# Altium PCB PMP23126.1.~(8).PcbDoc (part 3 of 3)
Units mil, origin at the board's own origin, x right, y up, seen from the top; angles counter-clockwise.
Board outline 1315.03 x 1390.8 mil, 6 copper layers (Top Layer, MidLayer1, MidLayer2, MidLayer3, MidLayer4, Bottom Layer), stack 72.6 mil thick; 49 components, 55 nets, 222 pads, 193 vias.
Unrouted connection lines stored in the file: 15.

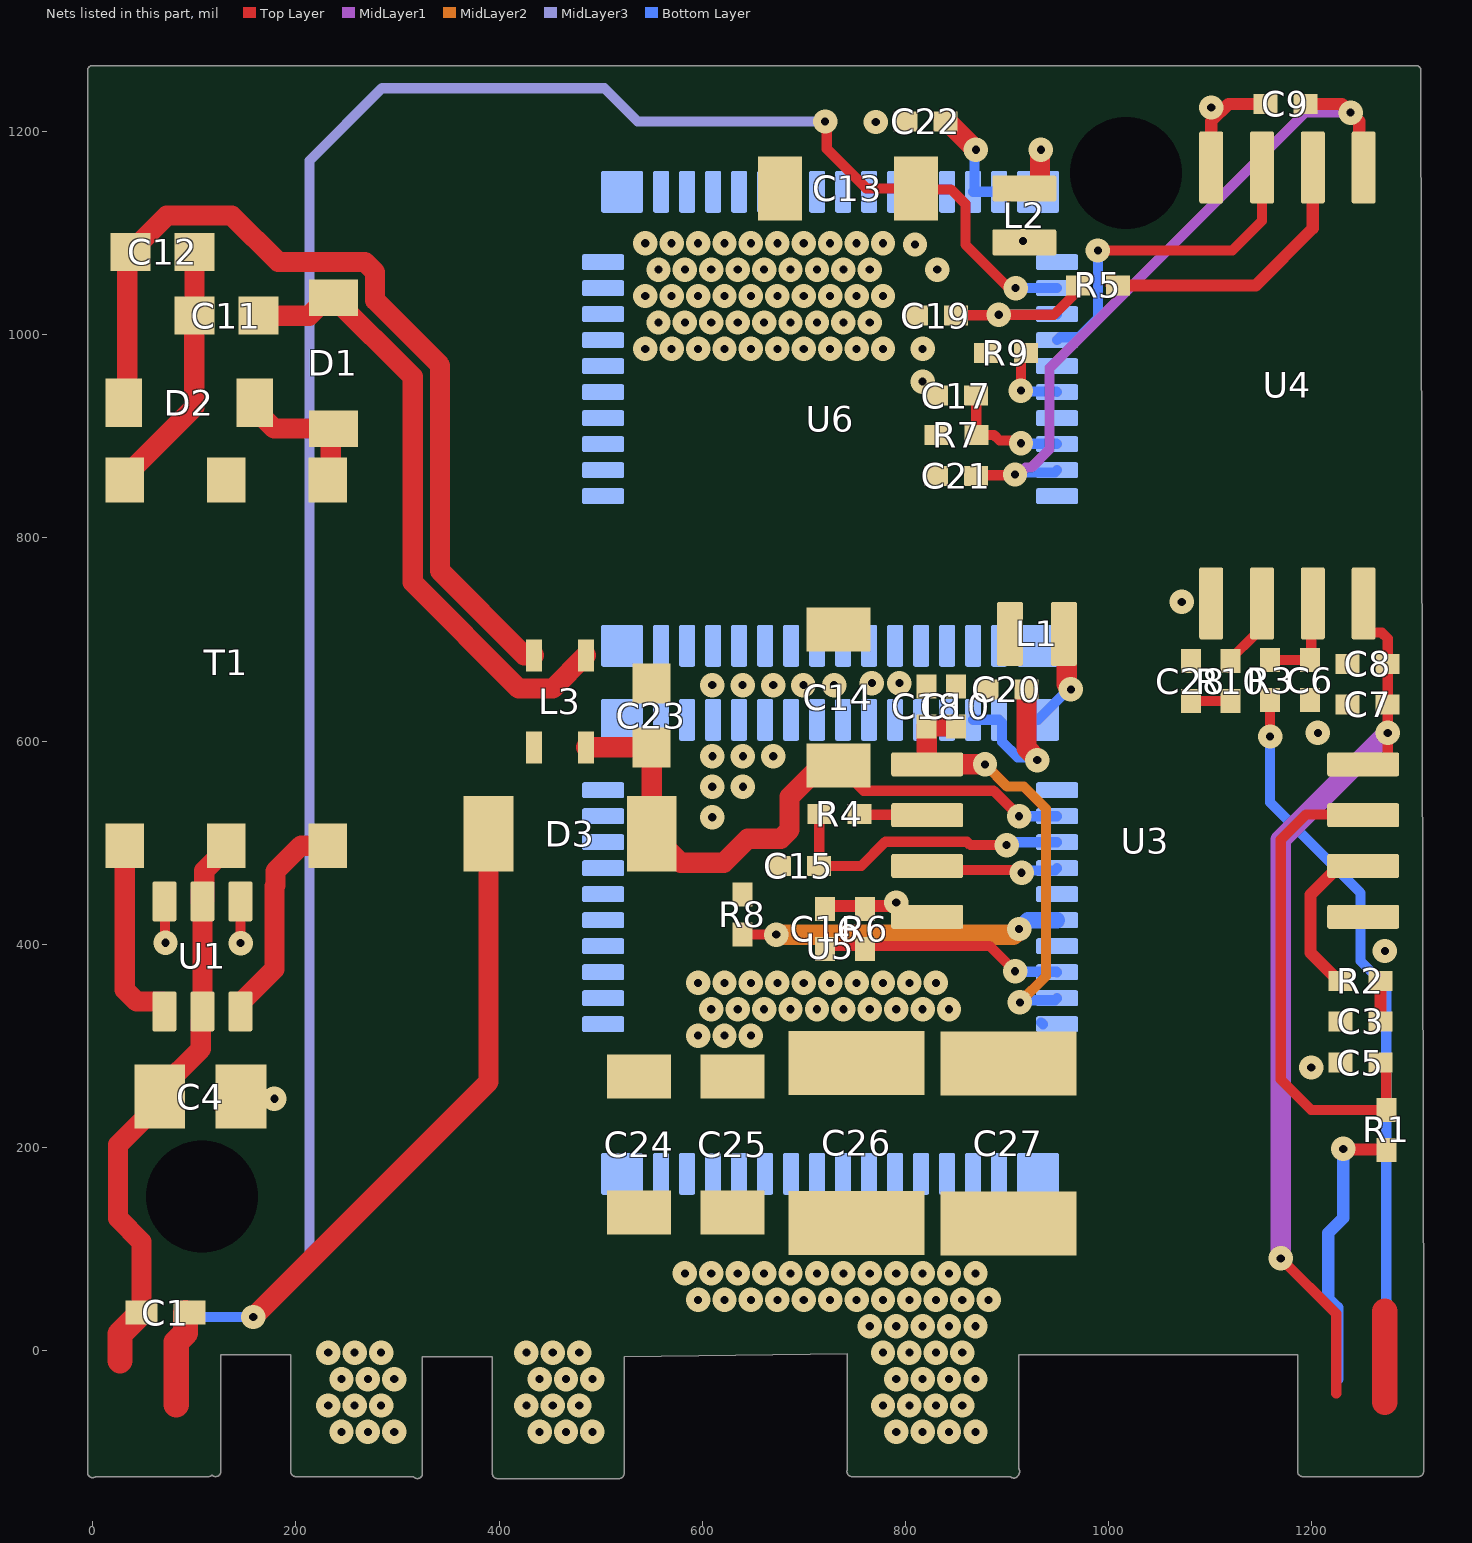
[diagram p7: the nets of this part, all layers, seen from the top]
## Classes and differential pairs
net class INGND: 3.3Vs _Bot_FET_FAULT1 _Top_FET_FAULT1 AGND LEG1_HS LEG1_LS NetC5_1 NetC6_1 NetR2_2 NetR10_2 NetU2_12 NetU3_12
net class PGND: 5V_L1 5Vp 12V FAULT_LS NetC17_2 NetC19_2 NetC22_1 NetL2_2 NetR5_1 NetR9_2 NetT1_4 NetT1_6 NetU2_5 NetU6_43 NetU6_47 NetU6_48 NetU6_52 PGND PGND_NC1 PGND_NC2 PGND_NC3 PGND_NC4 PGND_NC5 TEMP_LS
net class VHV: Vbulk+ VHV_NC1 VHV_NC2
net class VSW1NET: 5V_H1 12V ISO_12V_H1 NCT1 NetC11_1 NetC11_2 NetC12_2 NetC15_2 NetC16_2 NetC20_1 NetD1_2 NetL1_2 NetR4_2 NetR8_2 NetT1_5 NetU3_3 NetU3_5 NetU5_43 NetU5_47 NetU5_48 NetU5_52 SW1 SW1_NC1 SW1_NC2 SW1_NC3 SW1_NC4 SW1_NC5 SW1_NC6 SW1_NC7 TEMP_HS_NC1
component class LMG352X: U5 U6

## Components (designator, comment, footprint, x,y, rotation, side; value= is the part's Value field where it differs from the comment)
C1 "C1005X7R1H104K050BB" 0402 71.69,37.41 r0 top value=0.1uF
C3 "C1005C0G1H680J050BA" 0402L 1248,324.09 r180 top value=68pF
C4 "GCM21BR71C475KA73L" 0805_HV 106,250 r0 top value=4.7uF
C5 "04025A101FAT2A" 0402L 1247.9,283.5 r180 top value=100pF
C6 "04025A101FAT2A" 0402L 1198,660 r270 top value=100pF
C7 "C1005X7R1H104K050BB" 0402L 1255,636 r180 top value=0.1uF
C8 "C1005X7R1H104K050BB" 0402L 1255,676 r0 top value=0.1uF
C9 "C1005X7R1H104K050BB" 0402L 1174,1227 r0 top value=0.1uF
C10 "C1005X7R1H104K050BB" 0402L 849.62,634 r90 top value=0.1uF
C11 "C1608X5R1V475K080AC" 0603 131.62,1018.63 r180 top value=4.7uF
C12 "C1608X5R1V475K080AC" 0603 68.88,1081.48 r180 top value=4.7uF
C13 "C3216X7R1E106M160AE" 1206_190 743.36,1143.96 r180 top value=10uF
C14 "C3216X7R1E106M160AE" 1206_190 734,643 r90 top value=10uF
C15 "04025A101FAT2A" 0402L 695.25,477 r0 top value=100pF
C16 "04025A101FAT2A" 0402L 720.95,415 r270 top value=100pF
C17 "04025A101FAT2A" 0402L 850,940 r0 top value=100pF
C18 "CL05B224KO5NNNC" 0402L 820.93,634 r270 top value=0.22uF
C19 "04025A101FAT2A" 0402L 829.94,1018.63 r0 top value=100pF
C20 "GRT155R61E225KE13D" 0402L 899.5,650.82 r180 top value=2.2uF
C21 "CL05B224KO5NNNC" 0402L 850,861 r0 top value=0.22uF
C22 "GRT155R61E225KE13D" 0402L 820,1210 r180 top value=2.2uF
C23 "C1608X5R1V475K080AC" 0603 550,625 r90 top value=4.7uF
C24 "C1206C223KDRACTU" 1206_190 538,203 r90 top value=0.022uF
C25 "C1206C223KDRACTU" 1206_190 630,203 r90 top value=0.022uF
C26 "C1812W104KDRACTU" 1812_254 752,204.48 r90 top value=0.1uF
C27 "C1812W104KDRACTU" 1812_254 901.45,204 r90 top value=0.1uF
C28 "C1005C0G1H680J050BA" 0402L 1081,659 r90 top value=68pF
D1 "MBR0520LT1G" SOD-123 237,972 r270 top value=20V
D2 "MBR0520LT1G" SOD-123 95,933 r180 top value=20V
D3 "ES1JAF" SMAF 470,508.64 r180 top value=600V
L1 "SDEM20161T-4R7MS" FP-SDEM20161T-4R7MS_SMD2-MFG 929.44,705.4 r0 top
L2 "SDEM20161T-4R7MS" FP-SDEM20161T-4R7MS_SMD2-MFG 917.03,1117.39 r90 top
L3 "ACM2520-601-2P-T002" TDK_ACM2520-2P 460,639.13 r270 top
R1 "RC0402FR-0749R9L" 0402L 1273.29,217.19 r90 top value=49.9
R2 "CRCW0402300RJNED" 0402L 1247.9,364 r180 top value=300
R3 "RC0402FR-0749R9L" 0402L 1159,660 r90 top value=49.9
R4 "RC0402FR-0749R9L" 0402L 735,528 r0 top value=49.9
R5 "RC0402FR-0749R9L" 0402L 989.48,1048.39 r180 top value=49.9
R6 "ERJ-2RKF2003X" 0402L 760,415 r270 top value=200k
R7 "ERJ-2RKF2003X" 0402L 850.08,901.07 r0 top value=200k
R8 "ERJ-2GE0R00X" 0402L 639.59,429.42 r270 top value=0
R9 "ERJ-2GE0R00X" 0402L 899,982 r0 top value=0
R10 "CRCW0402300RJNED" 0402L 1120,659 r90 top value=300
T1 "760390014" Wurth_760390013 131.62,677 r270 top value=475uH
U1 "SN6505BDBVR" DBV0006A_N 108.09,388 r90 top
U3 "ISO7721FDWV" DWV0008A 1036,502 r0 top
U4 "ISO7721FDWV" DWV0008A 1176,950 r270 top
U5 "XMG3522R030QRQSTQ1" RQS0052A-MFG 725.84,397.43 r90 bottom
U6 "XMG3522R030QRQSTQ1" RQS0052A-MFG 725.84,917.17 r90 bottom

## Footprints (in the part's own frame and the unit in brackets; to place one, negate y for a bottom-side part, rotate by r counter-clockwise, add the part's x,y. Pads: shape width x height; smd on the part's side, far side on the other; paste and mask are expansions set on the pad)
0402 [mm] "0402 from SM-752 data"
  rect 0.8x0.6 smd: 1(-0.6,0) 2(0.6,0)
  silkscreen extent -1.22,-0.52 1.22,0.52, body extent -0.55,-0.3 0.55,0.3, height 0.6
0402L [mm] "0402 from SM-752 data"
  rect 0.6x0.5 smd: 1(-0.5,0) 2(0.5,0)
  body extent -0.55,-0.3 0.55,0.3, height 0.6
0603 [mm] "0603 from SM-752 data"
  rect 1x0.95 smd: 1(-0.8,0) 2(0.8,0)
  silkscreen extent -1.52,-0.69 1.52,0.69, body extent -0.87,-0.47 0.87,0.47, height 1
0805_HV [mil] "0805 with 30mil clearance between pads"
  rect 50x63 smd: 1(-40,0) 2(40,0)
  silkscreen extent -74,-40 74,40, body extent -43,-29 43,29, height 57
1206_190 [mm] "1206_190"
  rect 1.1x1.6 smd: 1(-1.7,0) 2(1.7,0)
  silkscreen extent -0.9,-1 0.9,1, body extent -1.75,-0.95 1.75,0.95, height 1.9
1812_254 [mm] "SMD, 2-Leads, Body 4.8x3.4mm"
  rect 1.6x3.4 smd: 1(-2,0) 2(2,0)
  silkscreen extent -0.8,-1.7 0.8,1.7, body extent -2.4,-1.7 2.4,1.7, height 2.54
DBV0006A_N [mm] "SOT23, 6-Leads, Body 2.9x1.6mm, Pitch 0.95mm, Lead Span 2.8mm, IPC Medium Density"
  rrect17% 1x0.6 smd: 1(-1.375,0.95) 2(-1.375,0) 3(-1.375,-0.95) 4(1.375,-0.95) 5(1.375,0) 6(1.375,0.95)
  silkscreen extent -1.68,-1.55 0.5,1.55, body extent -1.42,-1.46 1.42,1.46, height 1.12
DWV0008A [mm] "SOIC, 8-Leads, Body 5.95x7.6mm (max), Pitch 1.27mm"
  rrect17% 1.8x0.6 smd: 1(-5.45,1.905) 2(-5.45,0.635) 3(-5.45,-0.635) 4(-5.45,-1.905) 5(5.45,-1.905) 6(5.45,-0.635) 7(5.45,0.635) 8(5.45,1.905)
  silkscreen extent -6.25,-2.95 2.98,2.95, body extent -5.77,-2.92 5.77,2.93, height 2.67
FP-SDEM20161T-4R7MS_SMD2-MFG [mm]
  rrect15% 0.65x1.6 smd paste+0 mask+0: 1(-0.675,0) 2(0.675,0)
  silkscreen extent -1.05,-1.22 1.05,1.2, body extent -1.15,-0.95 1.15,0.95, height 0.25
RQS0052A-MFG [mm]
  rrect10% 1.05x1.05 smd paste+0 mask+0: 1(-5.675,5.2) 16(-5.675,-5.2) 27(5.675,-5.2) 42(5.675,5.2)
  rrect25% 1.05x0.4 smd paste+0 mask+0: 2(-5.675,4.225) 3(-5.675,3.575) 4(-5.675,2.925) 5(-5.675,2.275) 6(-5.675,1.625) 7(-5.675,0.975) 8(-5.675,0.325) 9(-5.675,-0.325) 10(-5.675,-0.975) 11(-5.675,-1.625) 12(-5.675,-2.275) 13(-5.675,-2.925) 14(-5.675,-3.575) 15(-5.675,-4.225) 28(5.675,-4.225) 29(5.675,-3.575) 30(5.675,-2.925) 31(5.675,-2.275) 32(5.675,-1.625) 33(5.675,-0.975) 34(5.675,-0.325) 35(5.675,0.325) 36(5.675,0.975) 37(5.675,1.625) 38(5.675,2.275) 39(5.675,2.925) 40(5.675,3.575) 41(5.675,4.225)
  rrect25% 0.4x1.05 smd paste+0 mask+0: 17(-1.935,-5.675) 18(-1.285,-5.675) 19(-0.635,-5.675) 20(0.015,-5.675) 21(0.665,-5.675) 22(1.315,-5.675) 23(1.965,-5.675) 24(2.615,-5.675) 25(3.265,-5.675) 26(3.915,-5.675) 43(3.915,5.675) 44(3.265,5.675) 45(2.615,5.675) 46(1.965,5.675) 47(1.315,5.675) 48(0.665,5.675) 49(0.015,5.675) 50(-0.635,5.675) 51(-1.285,5.675) 52(-1.935,5.675)
  silkscreen extent -6.9,-6.05 4.77,6.05, body extent -6,-6 6,6, height 1
SMAF [mm] "SMD, 2-Leads, Body 3.8x2.5mm"
  rect 1.24x1.89 smd: 1(-2.04,0) 2(2.04,0)
  silkscreen extent -3.4,-1.3 2.8,1.3, body extent -2.35,-1.25 2.35,1.25, height 1
SOD-123 [mm] "On Semi recommended land pattern"
  rect 0.915x1.22 smd: 1(-1.637,0) 2(1.637,0)
  silkscreen extent -2.74,-1.17 2.03,1.17, body extent -1.93,-0.9 1.93,0.9, height 1.35
TDK_ACM2520-2P [mm] "SMD, 4-Leads, Body 2.5x2mm"
  rect 0.8x0.4 smd: 1(-1.15,0.65) 2(-1.15,-0.65) 3(1.15,-0.65) 4(1.15,0.65)
  silkscreen extent -1.45,-1.2 1.45,1.4, body extent -1.35,-1.1 1.35,1.1, height 1.3
Wurth_760390013 [mil] "Wurth"
  rect 44x38 smd: 1(-180,100) 2(-180,0) 3(-180,-100) 4(180,-100) 5(180,0) 6(180,100)
  silkscreen extent -190,-133 85,145, body extent -198,-135 198,130, height 166

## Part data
C1 C7 C8 C9 C10: library part CMP-0006297-2, "CAP, CERM, 0.1 uF, 50 V, +/- 10%, X7R, 0402", Alternate Manufacturer="Wurth Elektronik", Alternate PartNumber=885012205037, Cap_Case=0402, Manufacturer=TDK, Supplier Part Number 1=445-5932-1-ND, TempCo=X7R, Tolerance_%=10%, Value1="0.039064 ohm", Value2=50V, ValueDisplayed=0.1uF
C3 C28: library part CMP-0006251-2, "CAP, CERM, 68 pF, 50 V, +/- 5%, C0G/NP0, 0402", Alternate Manufacturer=Murata, Alternate PartNumber=GRM1555C1H680JA01D, Cap_Case=0402, Manufacturer=TDK, Supplier Part Number 1=445-1245-1-ND, TempCo=C0G/NP0, Tolerance_%=5%, Value1=Unknown, Value2=50V, ValueDisplayed=68pF
C4: library part CMP-0008020-2, "CAP, CERM, 4.7 uF, 16 V, +/- 10%, X7R, AEC-Q200 Grade 1, 0805", Cap_Case=0805, Manufacturer=MuRata, Supplier Part Number 1=490-5332-1-ND, TempCo=X7R, Tolerance_%=10%, Value1=Unknown, Value2=16V, ValueDisplayed=4.7uF
C5 C6 C15 C16 C17 C19: library part CMP-0006196-2, "CAP, CERM, 100 pF, 50 V, +/- 1%, C0G/NP0, 0402", Cap_Case=0402, Manufacturer=AVX, Supplier Part Number 1=478-3658-1-ND, TempCo=C0G/NP0, Tolerance_%=1%, Value1=Unknown, Value2=50V, ValueDisplayed=100pF
C11 C12 C23: library part CMP-0007022-5, "CAP, CERM, 4.7 uF, 35 V, +/- 10%, X5R, 0603", Cap_Case=0603, Manufacturer=TDK, Supplier Part Number 1=445-9064-1-ND, TempCo=X5R, Tolerance_%=10%, Value1="0.003728 ohm", Value2=35V, ValueDisplayed=4.7uF
C13 C14: library part CMP-0008692-2, "CAP, CERM, 10 uF, 25 V, +/- 20%, X7R, 1206_190", Cap_Case=1206, Manufacturer=TDK, Supplier Part Number 1=445-6812-1-ND, TempCo=X7R, Tolerance_%=20%, Value1=Unknown, Value2=25V, ValueDisplayed=10uF
C18 C21: library part CMP-0860563-1, "CAP, CERM, 0.22 µF, 16 V,+/- 10%, X7R, 0402", Cap_Case=0402, Manufacturer="Samsung Electro-Mechanics", TempCo=X7R, Tolerance_%=10%, Value2=16V, ValueDisplayed=0.22µF
C20 C22: library part CMP-0006716-2, "CAP, CERM, 2.2 uF, 25 V, +/- 10%, X5R, AEC-Q200 Grade 3, 0402", Cap_Case=0402, Manufacturer=MuRata, Supplier Part Number 1=490-12267-1-ND, TempCo=X5R, Tolerance_%=10%, Value1=Unknown, Value2=25V, ValueDisplayed=2.2uF
C24 C25: library part CMP-0084048-1, "CAP, CERM, 0.022 µF, 1000 V,+/- 10%, X7R, AEC-Q200 Grade 1, 1206", Cap_Case=1206, Manufacturer=Kemet, TempCo=X7R, Tolerance_%=10%, Value2=1000V, ValueDisplayed=0.022µF
C26 C27: library part CMP-0009326-2, "CAP, CERM, 0.1 uF, 1000 V, +/- 10%, X7R, 1812", Cap_Case=1812, Manufacturer=Kemet, Supplier Part Number 1=399-6523-1-ND, TempCo=X7R, Tolerance_%=10%, Value1=Unknown, Value2=1000V, ValueDisplayed=0.1uF
D1 D2: library part CMP-0028524-2, "Diode, Schottky, 20 V, 0.5 A, SOD-123", Manufacturer="ON Semiconductor", Value1=0.5A, Value2=0.385V
D3: library part CMP-0029162-2, "Diode, Ultrafast, 600 V, 1 A, AEC-Q101, SMAF", Manufacturer="Fairchild Semiconductor", Value1=1A, Value2=1.7V
L1 L2: library part CMP-0089347-1, "4.7µH Unshielded Inductor 1.1A 426mOhm Max 0806 (2016 Metric)", Digikey Part Number=2037-SDEM20161T-4R7MSCT-ND, Manufacturer=Cyntec, Operating Temperature Range="-55°C to +125°C", Test Frequency=1MHz, Tolerance_%=20%
L3: library part CMP-0013161-2, "Coupled inductor, 0.2 A, 0.45 ohm, SMD", Manufacturer=TDK, Supplier Part Number 1=445-8930-1-ND
R1 R3 R4 R5: library part CMP-0026738-1, "RES, 49.9, 1%, 0.063 W, 0402", Manufacturer="Yageo America", Power_W=63mW, Supplier Part Number 1=311-49.9LRCT-ND, TempCo="100 ppm/C", Tolerance_%=1%, Value2=0.063W, Value_Code=49R9, ValueDisplayed=49.9
R2 R10: library part CMP-0026902-3, "RES, 300, 5%, 0.063 W, AEC-Q200 Grade 0, 0402", Manufacturer=Vishay-Dale, Power_W=63mW, Supplier Part Number 1=541-300JCT-ND, TempCo="200 ppm/C", Tolerance_%=5%, Value2=0.063W, Value_Code=300R, ValueDisplayed=300
R6 R7: library part CMP-0026677-1, "RES, 200 k, 1%, 0.1 W, 0402", Manufacturer=Panasonic, Power_W=100mW, Supplier Part Number 1=P200KLCT-ND, TempCo="100 ppm/C", Tolerance_%=1%, Value2=0.1W, Value_Code=200k
R8 R9: library part CMP-0026992-3, "RES, 0, 5%, 0.1 W, AEC-Q200 Grade 0, 0402", Manufacturer=Panasonic, Power_W=100mW, Supplier Part Number 1=P0.0JCT-ND, TempCo="600 ppm/C", Tolerance_%=5%, Value2=0.1W, Value_Code=0000, ValueDisplayed=0
T1: library part CMP-0030718-1, "Transformer, 475uH, SMT", Manufacturer="Wurth Elektronik", Supplier Part Number 1=732-4458-1-ND, ValueDisplayed=475uH
U1: library part CMP-0076095-1, "Low-Noise 1 A, 420 kHz Transformer Driver, DBV0006A (SOT-23-6)", Alternate Manufacturer="Texas Instruments", Alternate PartNumber=SN6505BDBVT
U3 U4: library part CMP-0085676-1, "High Speed, Robust EMC Reinforced Dual-Channel Digital Isolator, DWV0008A (SOIC-8)", Alternate Manufacturer="Texas Instruments", Alternate PartNumber=ISO7721FDWVR, Operating Temperature Range="-55 to 125 C", Rating=Catalog
U5 U6: library part CMP-0092112-1, "650-V 30-mΩ GaN FET with Integrated Driver, Protection, and Temperature Reporting", Manufacturer="Texas Instruments", Max Supply Voltage=18V, Min Supply Voltage=7.5V, Nominal Supply Current=700-16000uA, Operating Temperature Range="-40°C to +125°C", Output Voltage=520V, PartNumber=XMG3522R050QRQSTQ1

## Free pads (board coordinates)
  round 60 hole 110.24: 1(107.5,151.54) 1(1017,1159.25)

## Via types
v1: diameter 24, hole 8, Top Layer to Bottom Layer, 140 vias
v2: diameter 24, hole 8, Top Layer to Bottom Layer, tented both sides, 53 vias

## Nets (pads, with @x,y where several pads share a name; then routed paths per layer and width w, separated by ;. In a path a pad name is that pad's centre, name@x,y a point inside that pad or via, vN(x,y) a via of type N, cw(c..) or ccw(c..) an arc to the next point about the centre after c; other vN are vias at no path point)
3.3Vs: C7.1 C8.2 U3.8 U4.8 | length 911
  Top Layer w10: v2(1169.47,90.73) 1224,36.2 1224,-42 ; U3.8@1250.57,577 1267.87,577 1274.68,583.81 v2(1274.68,608) C7.1@1274.68,636 C8.2@1274.69,676 1274.69,700.84 1268.83,706.7 1257.81,706.7 1251,713.51 U4.8@1251,735.43
  MidLayer1 w20: v2(1169.47,90.73) 1169.47,502.79 v2(1274.68,608)
5V_H1: C10.1 C18.2 U3.1 U5.51 | length 440.9
  Top Layer w20: C10.1@849.62,614.32 C18.2@820.93,614.31 820.93,577.5 U3.1@821.43,577 v2(878.36,577)
  MidLayer2 w10: v2(878.36,577) 900.24,555.12 916.76,555.12 938.4,533.48 938.4,368.48 v2(912.66,342.74)
  Bottom Layer w10: v2(912.66,342.74) 914.7,344.79 947.22,344.79 U5.51@949.27,346.83
5V_L1: C9.2 C21.2 U4.1 U6.51 | length 713.8
  Top Layer w10: C21.2@869.69,861 870.32,861.64 907.2,861.64 v2(907.84,862.28)
  Top Layer w12: C9.2@1193.69,1227 1229.69,1227 v2(1238.19,1218.5) 1246.69,1210 1246.69,1168.88 U4.1@1251,1164.57
  MidLayer1 w10: v2(907.84,862.28) 911.63,862.28 918.43,869.08 923.76,869.08 941.84,887.16 941.84,967 1193.34,1218.5 v2(1238.19,1218.5)
  Bottom Layer w10: v2(907.84,862.28) 909.99,864.43 947.12,864.43 U6.51@949.27,866.58
5Vp: C1.1 C4.1 T1.5 U1.2 U1.5 | length 571.9
  Top Layer w20: C1.1@48.07,37.41 48.07,107.19 25,130.26 25,202.5 66,243.5 C4.1@66,250 66,256.5 106.28,296.78 106.28,324.18 U1.2@108.09,325.99 ; U1.5@106.38,442.13 U1.5@106.38,452.44 ; U1.2@108.09,333.87 U1.5@108.09,442.13 109.91,443.94 109.91,472.28 131.62,494 T1.5@131.62,497
  Top Layer w25: 27,-10 27,16.34 C1.1@48.07,37.41
12V: C13.1 D3.2 U6.44 | length 2744.8
  Top Layer w10: v2(720.95,1209.8) 722.63,1208.12 722.63,1182.8 761.47,1143.96 C13.1@810.29,1143.96 811.3,1142.95 844.91,1142.95 859.04,1128.82 859.04,1088.67 899.32,1048.39 905.74,1048.39 v2(908.42,1045.71)
  Top Layer w20: v2(158.08,33.03) 389.69,264.63 D3.2@389.69,508.64
  MidLayer3 w10: v2(158.08,33.03) 158.08,35.61 213.47,91 213.47,1171.28 284.69,1242.5 503.76,1242.5 536.46,1209.8 v2(720.95,1209.8)
  Bottom Layer w10: 84.19,-28.03 82.7,-26.54 82.7,15.75 99.98,33.03 v2(158.08,33.03) ; v2(908.42,1045.71) U6.44@949.27,1045.71
_Bot_FET_FAULT1: C28.1 R10.1 | length 39.3
  Top Layer w10: C28.1@1081.19,639.13 C28.1@1081,639.32 R10.1@1120,639.32
_Top_FET_FAULT1: C3.1 R2.1 | length 40
  Top Layer w12: R2.1@1267.58,364 1267.63,363.95 1267.63,324.14 C3.1@1267.68,324.09
AGND: C3.2 C5.2 C6.2 C7.2 C8.1 C28.2 U3.5 U4.5 | length 89.6
  Top Layer w25: 1271.9,-51 1271.9,38.61
  other v2: 1199.5,278.66 1271.9,393.35 1206,608 1072,737
FAULT_LS: U4.3 U6.46 | length 342.1
  Top Layer w10: v2(989.48,1082.82) 1121.82,1082.82 1151,1112 U4.3@1151,1164.57
  Bottom Layer w10: U6.46@949.27,994.53 952.14,997.4 970.91,997.4 989.48,1015.97 v2(989.48,1082.82)
ISO_12V_H1: C14.1 C23.1 D3.1 L3.4 U5.44 | length 639.9
  Top Layer w10: C14.1@734,576.07 759,551.08 886.86,551.08 v2(911.96,525.97)
  Top Layer w20: L3.4@485.59,593.85 549.65,593.85 C23.1@550,593.5 550.31,593.19 D3.1@550.31,508.64 578.87,480.09 621.07,480.09 644.82,503.84 677.32,503.84 685.98,512.51 685.98,545 717.05,576.07 C14.1@734,576.07
  Bottom Layer w10: v2(911.96,525.97) U5.44@949.27,525.97
LEG1_HS: R1.1 | length 279.8
  Top Layer w12: v2@1231.1,198.75 v2(1230.88,198.54) 1231.4,198.02 1272.78,198.02 R1.1@1273.29,197.5 R1.1@1273.51,197.29
  Bottom Layer w12: 1225,-28.03 1225,42.21 1216.2,51.01 1216.2,115.81 1230.88,130.49 v2(1230.88,198.54)
LEG1_LS: R3.1 | length 712.6
  Top Layer w10: v2(1159,604.48) R3.1@1159,640.32
  Bottom Layer w10: v2(1159,604.48) 1159,539.47 1247.9,450.57 1247.9,383.41 1273.29,358.02 1273.29,-24.96
NCT1: T1.2
NetC5_1: C5.1 R1.2 U3.7 | length 493.8
  Top Layer w10: U3.7@1250.57,527 1249.76,527.81 1194.49,527.81 1169.47,502.79 1169.47,266.86 1199.46,236.87 R1.2@1273.29,236.87 1273.29,278.66 1268.45,283.5 C5.1@1267.58,283.5 C5.1@1267.8,283.28
NetC6_1: C6.1 R3.2 U4.7 | length 98.1
  Top Layer w10: R3.2@1159,679.69 C6.1@1198,679.68 1199.5,681.18 1199.5,733.93 U4.7@1201,735.43 U4.7@1199.5,736.93
NetC11_1: C11.1 D1.1 L3.1 | length 621.3
  Top Layer w20: C11.1@163.12,1018.63 213.15,1018.63 231,1036.47 D1.1@237,1036.47 315,958.47 315,756.15 419.49,651.66 452.84,651.66 L3.1@485.59,684.4
NetC11_2: C11.2 C12.1 T1.3 | length 256.8
  Top Layer w20: T1.3@31.62,857 31.62,860 100.13,928.5 C11.2@100.13,1018.63 100.25,1018.75 100.25,1081.35 C12.1@100.38,1081.48 C12.1@103.07,1078.79
NetC12_2: C12.2 D2.2 L3.2 | length 877.2
  Top Layer w20: D2.2@30.53,933 33.96,936.43 33.96,1078.05 C12.2@37.39,1081.48 73.09,1117.18 137.06,1117.18 182.76,1071.48 268.06,1071.48 278.02,1061.52 278.02,1033.64 342,969.65 342,767.33 424.93,684.4 L3.2@434.41,684.4
NetC15_2: C15.2 R4.1 U5.45 | length 300.7
  Top Layer w10: R4.1@709.38,530 R4.1@711.38,528 ; R4.1@715.31,528 715.13,527.81 715.13,477.19 C15.2@714.94,477 756.48,477 780.29,500.81 860.66,500.81 863.92,497.55 v2(899.58,497.55)
  Bottom Layer w10: v2(899.58,497.55) 903.37,497.55 906.2,500.38 U5.45@949.27,500.38
NetC16_2: C16.2 R6.2 U5.50 | length 241.9
  Top Layer w10: C16.2@720.95,391.38 C16.2@722.95,389.38 ; C16.2@720.95,398.31 760,398.31 883,398.31 v2(907.94,373.38)
  Bottom Layer w10: v2(907.94,373.38) 908.42,372.9 948.79,372.9 U5.50@949.27,372.43
NetC17_2: C17.2 R7.2 U6.50 | length 122.2
  Top Layer w10: R7.2@869.69,901 C17.2@869.69,940 ; R7.2@871.54,901.08 887.29,901.08 892.61,895.76 911.14,895.76 v2(913.82,893.08)
  Bottom Layer w10: v2@911.96,893 912.38,892.58 948.85,892.58 U6.50@949.27,892.17
NetC19_2: C19.2 R5.2 U6.45 | length 189.2
  Top Layer w10: C19.2@850.04,1018.21 C19.2@849.62,1018.63 850.08,1019.08 891.36,1019.08 v2(891.81,1019.53) 946.32,1019.53 R5.2@969.8,1043.01 ; R5.2@969.8,1048.39 R5.2@970.21,1047.97
  Bottom Layer w10: v2(891.81,1019.53) 892.1,1019.83 948.97,1019.83 U6.45@949.27,1020.12
NetC20_1: C20.1 U5.40 U5.41 | length 164.6
  Top Layer w20: C20.1@919.18,650.82 919.18,592.82 929.74,582.26 v2(929.74,581.18)
  Bottom Layer w10: U5.40@866.59,620.85 U5.41@892.18,620.85 895.06,617.98 895.06,599.26 910.46,583.86 927.06,583.86 v2(929.74,581.18)
NetC22_1: C22.1 U6.40 U6.41 | length 109.4
  Top Layer w20: C22.1@839.69,1210 841.34,1210 v2@869.31,1182.03
  Bottom Layer w10: v2(869.31,1182) 867.95,1180.64 867.95,1141.95 U6.40@866.59,1140.59 U6.41@892.18,1140.59
NetD1_2: D1.2 D2.1 T1.1 | length 144.4
  Top Layer w20: D2.1@159.47,933 159.47,927 178.93,907.53 D1.2@237,907.53 234.31,904.84 234.31,859.69 T1.1@231.62,857
NetL1_2: L1.2 U5.42 | length 125.8
  Top Layer w20: L1.2@958.81,726.9 956.02,724.1 L1.2@956.02,705.4 958.81,702.61 958.81,655.94 962.85,651.9 v2(962.85,650.82) v2@962.09,651.58
  Bottom Layer w10: U5.42@930.57,620.85 960.54,650.82 v2(962.85,650.82)
NetL2_2: L2.2 U6.42 | length 94.7
  Top Layer w20: L2.2@917.03,1143.96 929.72,1143.96 932.52,1146.76 932.52,1181.23 v2(933.28,1182)
  Bottom Layer w10: U6.42@930.57,1140.59 933.28,1143.31 v2(933.28,1182)
NetR2_2: R2.2 U3.6 | length 161.7
  Top Layer w12: R2.2@1228.21,364 1226.25,364 1198.69,391.56 1198.69,448.74 1226.94,477 U3.6@1250.57,477
NetR4_2: R4.2 U3.2 | length 67.2
  Top Layer w10: R4.2@754.69,528 755.19,527.5 820.93,527.5 U3.2@821.43,527
NetR5_1: R5.1 U4.2 | length 281.2
  Top Layer w12: R5.1@1003.08,1048.39 1144.78,1048.39 1201,1104.61 U4.2@1201,1164.57
NetR8_2: R8.2 U5.48 | length 319.6
  Top Layer w10: R8.2@639.38,409.95 R8.2@639.59,409.73 639.75,409.58 672.7,409.58 v2(672.86,409.42) v2@673.07,409.63
  MidLayer2 w10: v2@672,415 v2@672.86,415
  MidLayer2 w20: v2(672.86,409.42) 906.38,409.42 v2(911.96,415)
  Bottom Layer w10: U5.48@947.57,425.3 U5.48@949.27,423.61
  Bottom Layer w16: v2(911.96,415) 920.57,423.61 U5.48@949.27,423.61
NetR9_2: R9.2 U6.48 | length 75.6
  Top Layer w10: v2(913.66,944.84) 913.66,977.16 918.5,982 R9.2@918.69,982
  Bottom Layer w10: v2(913.66,944.84) 914.41,944.09 948.52,944.09 U6.48@949.27,943.35
NetR10_2: R10.2 U4.6 | length 69.6
  Top Layer w10: R10.2@1120,678.69 1120,680.65 1144.19,704.84 1144.19,728.62 U4.6@1151,735.43
NetT1_4: T1.4 U1.1 | length 194.3
  Top Layer w20: T1.4@31.62,497 31.62,355.27 43.34,343.55 68.88,343.55 70.69,341.74 U1.1@70.69,333.87
NetT1_6: T1.6 U1.3 | length 214.4
  Top Layer w20: U1.3@145.5,333.87 145.5,341.74 178.96,375.2 178.96,456.96 180,458 180,471.91 205.09,497 T1.6@231.62,497
NetU3_3: U3.3 U5.46 | length 132.5
  Top Layer w10: U3.3@821.43,477 825.44,473 911.72,473 v2(914.4,470.32)
  Bottom Layer w10: v2(914.4,470.32) 916.63,472.55 947.03,472.55 U5.46@949.27,474.79
PGND: C1.2 C4.2 C9.1 C13.2 C17.1 C19.1 C21.1 C22.2 C24.2 C25.2 C26.2 C27.2 L2.1 R7.1 R9.1 U1.4 U1.6 U4.4 U6.18 U6.19 U6.20 U6.21 U6.22 U6.23 U6.24 U6.25 U6.26 U6.28 U6.29 U6.30 U6.31 U6.32 U6.33 U6.34 U6.35 U6.36 U6.37 U6.38 U6.39 | length 294.9
  Top Layer w10: U1.6@70.69,442.13 71.19,441.63 71.19,402 v2(71.69,401.5) ; U1.4@145.5,442.13 145.6,442.03 145.6,401.18 v2(145.71,401.07)
  Top Layer w12: C1.2@95.32,37.41 C1.2@99.9,32.83 ; U4.4@1101,1164.57 1101,1210 1118,1227 C9.1@1154.32,1227
  Top Layer w20: C1.2@91.38,37.41 C1.2@95.32,37.41 ; v2(915.78,1092.07) L2.1@917.03,1090.81
  Top Layer w25: 82.46,-53.28 82.46,8.46 91.38,17.38 C1.2@91.38,37.41
  Bottom Layer w10: 146,347 146.25,347.25
  other v1: 439.94,-80.03 465.94,-80.03 491.94,-80.03 426.94,-54.03 452.94,-54.03 478.94,-54.03 439.94,-28.03 465.94,-28.03 491.94,-28.03 426.94,-2.03 452.94,-2.03 478.94,-2.03 595.94,309.97 621.94,309.97 647.94,309.97 608.94,335.97 634.94,335.97 660.94,335.97 686.94,335.97 712.94,335.97 738.94,335.97 764.94,335.97 790.94,335.97 816.94,335.97 842.94,335.97 595.94,361.97 621.94,361.97 647.94,361.97 673.94,361.97 699.94,361.97 725.94,361.97 751.94,361.97 777.94,361.97 803.94,361.97 829.94,361.97 543.94,985.97 569.94,985.97 595.94,985.97 621.94,985.97 647.94,985.97 673.94,985.97 699.94,985.97 725.94,985.97 751.94,985.97 777.94,985.97 556.94,1011.97 582.94,1011.97 608.94,1011.97 634.94,1011.97 660.94,1011.97 686.94,1011.97 712.94,1011.97 738.94,1011.97 764.94,1011.97 543.94,1037.97 569.94,1037.97 595.94,1037.97 621.94,1037.97 647.94,1037.97 673.94,1037.97 699.94,1037.97 725.94,1037.97 751.94,1037.97 777.94,1037.97 556.94,1063.97 582.94,1063.97 608.94,1063.97 634.94,1063.97 660.94,1063.97 686.94,1063.97 712.94,1063.97 738.94,1063.97 764.94,1063.97 543.94,1089.97 569.94,1089.97 595.94,1089.97 621.94,1089.97 647.94,1089.97 673.94,1089.97 699.94,1089.97 725.94,1089.97 751.94,1089.97 777.94,1089.97
  other v2: 178.93,247.88 816.94,953.78 816.94,985.97 831.31,1063.97 809.43,1088.67 770.86,1209.3 1101,1223.51
PGND_NC1: U6.17
PGND_NC2: U6.27
PGND_NC3: U6.43
PGND_NC4: U6.47
PGND_NC5: U6.52
SW1: C10.2 C14.2 C15.1 C16.1 C18.1 C20.2 C23.2 L1.1 L3.3 R6.1 R8.1 U3.4 U5.18 U5.19 U5.20 U5.21 U5.22 U5.23 U5.24 U5.25 U5.26 U5.28 U5.29 U5.30 U5.31 U5.32 U5.33 U5.34 U5.35 U5.36 U5.37 U5.38 U5.39 U6.2 U6.3 U6.4 U6.5 U6.6 U6.7 U6.8 U6.9 U6.10 U6.11 U6.12 U6.13 U6.14 U6.15 | length 107.1
  Top Layer w12: C16.1@720.95,437.68 760,437.68 767.29,437.68 787.13,437.68 797.81,427 U3.4@821.43,427 ; C20.2@873.74,650.82 C20.2@875.88,650.82
  other v1: 244.94,-80.03 270.94,-80.03 296.94,-80.03 231.94,-54.03 257.94,-54.03 283.94,-54.03 244.94,-28.03 270.94,-28.03 296.94,-28.03 231.94,-2.03 257.94,-2.03 283.94,-2.03
  other v2: 790.94,441 609.89,525 609.89,554.95 640,554.95 610,585 640,585 669.89,585 609.89,655 639.83,655 669.89,655 699.52,655 729.79,655 766.94,657 794,657
SW1_NC1: U5.17
SW1_NC2: U5.27
SW1_NC3: U5.43
SW1_NC4: U5.47
SW1_NC5: U5.52 | length 2.6
  Bottom Layer w10: U5.52@933.6,323.09 U5.52@935.44,321.24
SW1_NC6: U6.1
SW1_NC7: U6.16
TEMP_HS_NC1: U5.49
TEMP_LS: U6.49
Vbulk+: C24.1 C25.1 C26.1 C27.1 U5.2 U5.3 U5.4 U5.5 U5.6 U5.7 U5.8 U5.9 U5.10 U5.11 U5.12 U5.13 U5.14 U5.15
  other v1: 790.94,-80.03 816.94,-80.03 842.94,-80.03 868.94,-80.03 777.94,-54.03 803.94,-54.03 829.94,-54.03 855.94,-54.03 790.94,-28.03 816.94,-28.03 842.94,-28.03 868.94,-28.03 777.94,-2.03 803.94,-2.03 829.94,-2.03 855.94,-2.03 764.94,23.97 790.94,23.97 816.94,23.97 842.94,23.97 868.94,23.97 595.94,49.97 621.94,49.97 647.94,49.97 673.94,49.97 699.94,49.97 725.94,49.97 751.94,49.97 777.94,49.97 803.94,49.97 829.94,49.97 855.94,49.97 881.94,49.97 582.94,75.97 608.94,75.97 634.94,75.97 660.94,75.97 686.94,75.97 712.94,75.97 738.94,75.97 764.94,75.97 790.94,75.97 816.94,75.97 842.94,75.97 868.94,75.97
VHV_NC1: U5.1
VHV_NC2: U5.16

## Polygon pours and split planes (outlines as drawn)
PGND on Bottom Layer "PGND_L06_P098" (solid, remove dead copper, pour order 98): 1119.01,1063.99 1002.06,1063.99 891.52,951 831.31,951 831.31,1259.84 1158.08,1259.84 1158.08,1103.06
Vbulk+ on Bottom Layer "VBULK+_L06_P077" (solid, remove dead copper, pour order 77): 532.18,202.12 499.28,169.21 499.28,84.85 582.94,1.19 583.75,2 747.81,2 747.81,-116.6 751.64,-120.43 906.71,-120.43 906.71,-0.23 907.94,1 979.32,1 979.32,168.74 945.94,202.12
PGND on Bottom Layer "PGND_L06_P065" (solid, remove dead copper, pour order 65): 495,14.13 523.17,-14.04 523.17,-119 390.96,-119 390.96,-0.93 404.94,-0.93 420,14.13
AGND on Bottom Layer "AGND_L06_P061" (solid, remove dead copper, pour order 61): 1027.98,724.65 1030.65,724.65 1060,754 1277,754 1307,724 1290,707 1290,5.98 1027.98,5.98
SW1 on Bottom Layer "SW1_L06_P048" (solid, pour order 48): 293,14.13 353,-45.87 352.48,-51.23 352.48,-119 192.48,-119 192.48,-20.39 227,14.13
SW1 on Bottom Layer "SW1_L06_P036" (solid, remove dead copper, pour order 36): 542.54,374.6 463.9,295.96 463.9,698.52 497.16,731.78 895.27,731.78 904.27,722.78 904.17,642.17 847.78,585.4 753.34,585.4
PGND on Bottom Layer "PGND_L06_P037" (solid, remove dead copper, pour order 37): 859,951 838,930 811,930 797,944 797,1104 789.82,1104 789.82,839.68 747.14,797 491.21,797 490.21,796 463,823.21 463,1164.28 469.85,1164.28 550.12,1244.55 859,1244.55
PGND on Bottom Layer "PGND_L06_P009" (solid, remove dead copper, pour order 9): 0,631 0,1 184,1 185,2 185,631
SW1 on Bottom Layer "SW1_L06_P122" (solid, pour order 122): 206.61,442.37 474.24,710 485,710 485,687.65 544.43,628.22 544.43,379.43 352.48,187.48 352.48,-118.8 206.61,-118.8
PGND on MidLayer2 "PGND_L03_P094" (solid, remove dead copper, pour order 94): 747.14,1259.84 747.14,1153.14 803.05,1097.23 823.84,1118.03 823.84,1259.84
Vbulk+ on MidLayer2 "VBULK+_L03_P074" (solid, remove dead copper, pour order 74): 569.94,100.96 569.94,14.19 582.94,1.19 583.75,2 747.81,2 747.81,-116.6 751.64,-120.43 906.71,-120.43 906.71,-0.23 907.94,1 979.32,1 979.32,100.96
PGND on MidLayer2 "PGND_L03_P069" (solid, remove dead copper, pour order 69): 1076.97,1259.84 1076.97,1125.84 823.84,1125.84 799,1101 799,853 952.97,853 953.9,853.93 953.9,953.9 1063.84,1063.84 1302.97,1063.84 1302.97,1258.87 1302,1259.84
PGND on MidLayer2 "PGND_L03_P063" (solid, remove dead copper, pour order 63): 390.96,14.13 390.96,-119 523.17,-119 523.17,14.13
SW1 on MidLayer2 "SW1_L03_P039" (solid, pour order 39): 207.77,375.22 207.77,442.37 497.8,732.4 742.79,732.4 742.79,577.79 540.23,375.23
SW1 on MidLayer2 "SW1_L03_P040" (solid, pour order 40): 352.48,187.48 544.43,379.43 544.43,442.37 206.61,442.37 206.61,-118.8 352.48,-118.8
AGND on MidLayer2 "AGND_L03_P013" (solid, remove dead copper, pour order 13): 1027,853 1027,1 1305,1 1305,851.27 1303.27,853
PGND on MidLayer2 "PGND_L03_P010" (solid, remove dead copper, pour order 10): 0,634 185,634 185,1 8,1 0,9
SW1 on MidLayer2 "SW1" (solid, remove dead copper, pour order 108): 747.81,682 747.81,682.25 758.56,693 936,693 947,682 947,646.85 976,617.85 976,455 946,425 685.37,425 668,442.37 668,496 748,576 748,682
SW1 on MidLayer2 "SW1_L03_P114" (solid, remove dead copper, pour order 114): 630,693 629.02,693 595.94,659.92 595.94,503.87 608.94,490.87 655.31,490.87 742.79,578.35 742.79,682.21 732,693
SW1 on MidLayer2 "SW1_L03_P112" (solid, remove dead copper, pour order 112): 630,693 629.02,693 595.94,659.92 595.94,503.87 608.94,490.87 655.31,490.87 742.79,578.35 742.79,682.21 732,693
PGND on MidLayer3 "PGND_L04_P095" (solid, remove dead copper, pour order 95): 750.63,1263.72 750.63,1149.65 802.86,1097.42 827.34,1121.9 827.34,1263.72
PGND on MidLayer3 "PGND_L04_P093" (solid, remove dead copper, pour order 93): 1076.97,1259.84 1076.97,1125.84 823.84,1125.84 799,1101 799,853 952.97,853 953.9,853.93 953.9,953.9 1063.84,1063.84 1302.97,1063.84 1302.97,1258.87 1302,1259.84
Vbulk+ on MidLayer3 "VBULK+_L04_P075" (solid, remove dead copper, pour order 75): 565,100.96 565,19.13 582.94,1.19 583.75,2 747.81,2 747.81,-116.6 751.64,-120.43 906.71,-120.43 906.71,-0.23 907.94,1 979.32,1 979.32,100.96
PGND on MidLayer3 "PGND_L04_P064" (solid, remove dead copper, pour order 64): 390.96,14.13 390.96,-119 523.17,-119 523.17,14.13
AGND on MidLayer3 "AGND_L04_P059" (solid, remove dead copper, pour order 59): 1032.5,851.27 1032.5,5.85 1300.15,5.85 1303.28,2.72 1303.28,846.57
SW1 on MidLayer3 "SW1_L04_P046" (solid, pour order 46): 192.48,14.13 342.64,14.13 352.48,14.13 352.48,-119 192.48,-119
PGND on MidLayer3 "PGND_L04_P011" (solid, remove dead copper, pour order 11): 0,634 192.48,634 192.48,1 0,1
SW1 on MidLayer3 "SW1" (solid, remove dead copper, pour order 110): 747.81,682 747.81,682.25 758.56,693 936,693 947,682 947,646.85 976,617.85 976,455 946,425 685.37,425 668,442.37 668,496 748,576 748,682
SW1 on MidLayer3 "SW1_L04_P116" (solid, remove dead copper, pour order 116): 630,693 629.02,693 595.94,659.92 595.94,503.87 608.94,490.87 655.31,490.87 742.79,578.35 742.79,682.21 732,693
PGND on MidLayer3 "PGND_L04_P120" (solid, remove dead copper, pour order 120): 665.11,388.69 850.37,388.69 865.22,373.84 865.22,275 820.22,230 559.96,230.26 551.18,221.48 551.18,-119 391.18,-119 386.22,-114.04 386.22,1105.32 420.91,1140 756.78,1140 791.16,1106.56 791.16,873.7 584.68,667.22 585.22,666.68 585.22,468.58
no net on Top Solder "NONET_L-01_P-001" (solid): 1191,1 1191,-119 1304.8,-119 1305,-118.8 1305,1
no net on Top Solder "NONET_L-01_P-001" (solid): 747.44,-0.93 747.44,-120.93 907.44,-120.93 907.44,-0.93
no net on Top Solder "NONET_L-01_P-001" (solid): 393.4,1 393.4,-119 523.17,-119 523.17,1
no net on Top Solder "NONET_L-01_P-001" (solid): 194.92,1 194.92,-119 324.69,-118.83 324.69,1
no net on Top Solder "NONET_L-01_P-001" (solid): -5.91,-1.71 -5.91,-120.15 121.19,-120.15 121.19,-1.71
SW1 on Top Layer "SW1_L01_P082" (solid, remove dead copper, pour order 82): 599.59,677 590,667.41 590,520 598.58,511.42 600,511.42 618.42,511.42 683,576 683,601.9 688.1,607 714,607 742.59,635.59 742.59,667.41 733,677
Vbulk+ on Top Layer "VBULK+_L01_P072" (solid, remove dead copper, pour order 72): 500.6,170.53 499.28,169.21 499.28,84.85 582.94,1.19 583.75,2 747.81,2 747.81,-116.6 751.64,-120.43 906.71,-120.43 906.71,-0.23 907.94,1 979.32,1 979.32,168.74 977.53,170.53
PGND on Top Layer "PGND_L01_P070" (solid, remove dead copper, pour order 70): 873.74,1116.88 873.98,1116.63 873.98,1073.72 955.89,1073.72 958.61,1071 958.61,1128.43 875.13,1128.43 873.74,1129.83
PGND on Top Layer "PGND_L01_P056" (solid, remove dead copper, pour order 56): 1009.17,1078.05 1014.16,1259.84 1302,1259.84 1302,972 1181.27,851.27 798,851.27 798,1106.56
PGND on Top Layer "PGND_L01_P054" (solid, remove dead copper, pour order 54): 17,465 20.29,468.29 160.79,468.29 192.48,438 192.48,84 119.48,11 116,10 75,10 75,67 17,125
PGND on Top Layer "PGND_L01_P053" (solid, remove dead copper, pour order 53): 517.94,954.06 517.94,1125.84 619.1,1227 792.69,1227 792.69,954.06
AGND on Top Layer "AGND_L01_P050" (solid, remove dead copper, pour order 50): 1038,772 1061,795 1106.1,795 1190.1,711 1302,711 1302,7.99 1304.99,5 1027,5 1027,205.67 1038,216.67
PGND on Top Layer "PGND_L01_P043" (solid, remove dead copper, pour order 43): 390.96,14.13 390.96,-119 523.17,-119 523.17,14.13
SW1 on Top Layer "SW1_L01_P042" (solid, pour order 42): 295,14.13 295,13 342.64,-35 342.64,-119 192.48,-119 192.48,-17.39 224,14.13
PGND on Top Layer "PGND_L01_P030" (solid, remove dead copper, pour order 30): 486.17,386 918.5,386 987.44,317.06 987.44,230.32 499.28,230.32 487.65,241.95
SW1 on Top Layer "SW1" (solid, remove dead copper, pour order 100): 662.94,490.78 626,453.84 626,438 634,430 702.38,430 717.38,415 805,415 813,423 813,438 795,456 703.29,456 689.87,469.42 689.87,485.88 684.97,490.78
SW1 on Top Layer "SW1" (solid, remove dead copper, pour order 102): 712.94,682 587.21,682 571.76,666.55 571.76,631.76 560,620 480,620 460,600 460,575 455,570 430,570 420,580 420,620.45 435.67,636.13 464.43,636.13 505,676.69 505,715 531,741 897.25,741 912,726.25 912,673.86 897.25,659.11 897.25,644 885.25,632 759.61,632 748,643.61 748,671 737,682
PGND on MidLayer4 "PGND_L05_P096" (solid, remove dead copper, pour order 96): 897.01,1125.84 894.16,1125.84 775,1245 265,1245 45,1025 45,250 70,225 180,225 190,235 190,1054.41 310.59,1175 748.29,1175 799,1124.29 799,853 952.97,853 953.9,853.93 953.9,953.9 1063.84,1063.84 1302.97,1063.84 1302.97,1258.87 1302,1259.84 1076.97,1259.84 1076.97,1125.84
SW1 on MidLayer4 "SW1_L05_P078" (solid, remove dead copper, pour order 78): 630,693 629.02,693 595.94,659.92 595.94,503.87 608.94,490.87 655.31,490.87 742.79,578.35 742.79,682.21 732,693
Vbulk+ on MidLayer4 "VBULK+_L05_P076" (solid, remove dead copper, pour order 76): 565,109.99 565,19.13 582.94,1.19 583.75,2 747.81,2 747.81,-116.6 751.64,-120.43 906.71,-120.43 906.71,-0.23 907.94,1 979.32,1 979.32,109.99
AGND on MidLayer4 "AGND_L05_P060" (solid, remove dead copper, pour order 60): 1027,853 1027,6.95 1028.95,5 1304.99,5 1304.99,851.28 1303.27,853
SW1 on MidLayer4 "SW1_L05_P047" (solid, pour order 47): 192.38,14.03 342.54,14.03 352.38,14.03 352.38,-119.1 192.38,-119.1
SW1 on MidLayer4 "SW1" (solid, remove dead copper, pour order 104): 747.81,682 747.81,682.25 758.56,693 936,693 947,682 947,646.85 976,617.85 976,455 946,425 685.37,425 668,442.37 668,496 748,576 748,682
PGND on MidLayer4 "PGND_L05_P118" (solid, remove dead copper, pour order 118): 665.11,388.69 850.37,388.69 865.22,373.84 865.22,275 820.22,230 559.96,230.26 551.18,221.48 551.18,-119 391.18,-119 386.22,-114.04 386.22,1105.32 420.91,1140 756.78,1140 791.16,1106.56 791.16,873.7 584.68,667.22 585.22,666.68 585.22,468.58
PGND on MidLayer1 "PGND_L02_P091" (solid, remove dead copper, pour order 91): 747.14,1259.84 747.14,1195.64 798.42,1195.64 799,1196.22 799,853 952.97,853 952.97,997.4 954.89,997.4 1181.27,1223.78 1181.27,1259.84
Vbulk+ on MidLayer1 "VBULK+_L02_P073" (solid, remove dead copper, pour order 73): 565,109.99 565,19.86 583.67,1.19 584.48,2 748.54,2 748.54,-116.6 752.37,-120.43 907.44,-120.43 907.44,-0.23 908.67,1 980.04,1 980.04,109.99
AGND on MidLayer1 "AGND_L02_P058" (solid, remove dead copper, pour order 58): 1032.5,840.99 1033.25,841.73 1033.25,852.14 1301.13,852.14 1305,848.27 1305,-3.19 1036.69,-3.19 1032.5,1
PGND on MidLayer1 "PGND_L02_P057" (solid, remove dead copper, pour order 57): 16.5,632.34 16,631.84 16,5 188.48,5 192.38,1.1 192.38,631
SW1 on MidLayer1 "SW1_L02_P045" (solid, pour order 45): 192.48,14.13 342.64,14.13 342.64,-119 192.48,-119
SW1 on MidLayer1 "SW1" (solid, remove dead copper, pour order 106): 747.81,682 747.81,682.25 758.56,693 936,693 947,682 947,646.85 976,617.85 976,455 946,425 685.37,425 668,442.37 668,496 748,576 748,682
PGND on MidLayer1 "PGND_L02_P080" (solid, remove dead copper, pour order 80): 664.88,388.69 850.14,388.69 865,373.84 865,275 820,230 559.74,230.26 550.96,221.48 550.96,-119 390.96,-119 386,-114.04 386,1105.32 420.68,1140 756.56,1140 790.94,1106.56 790.94,873.7 584.46,667.22 585,666.68 585,468.58
no net on Bottom Solder "NONET_L-01_P-001" (solid): 1191,1 1191,-119 1304.8,-119 1305,-118.8 1305,1
no net on Bottom Solder "NONET_L-01_P-001" (solid): -5.33,-2.97 -5.33,-122.97 124.44,-122.8 124.44,-2.97
no net on Bottom Solder "NONET_L-01_P-001" (solid): 747.44,-0.93 747.44,-120.93 907.44,-120.93 907.44,-0.93
no net on Bottom Solder "NONET_L-01_P-001" (solid): 393.4,1 393.4,-119 523.17,-119 523.17,1
no net on Bottom Solder "NONET_L-01_P-001" (solid): 194.92,1 194.92,-119 324.69,-118.83 324.69,1

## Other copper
Top Layer:
  region net 3.3Vs: 1210.5,0 1235.5,0 1235.5,-103.71 1210.5,-103.71
  region net AGND: 1259.4,0 1284.4,0 1284.4,-103.71 1259.4,-103.71
  region net PGND: 70.2,-0.93 95.2,-0.93 95.2,-105.64 70.2,-105.64
  region net 5Vp: 15,-0.08 40,-0.08 40,-104.79 15,-104.79
Bottom Layer:
  region: 40.29,0.5 15.29,0.5 15.29,-103.21 40.29,-103.21
  region net LEG1_HS: 1235.17,1 1210.17,1 1210.17,-103.71 1235.17,-103.71
  region net LEG1_LS: 1283.5,1 1258.5,1 1258.5,-103.71 1283.5,-103.71
  region net 12V: 96.69,1.12 71.69,1.12 71.69,-103.59 96.69,-103.59

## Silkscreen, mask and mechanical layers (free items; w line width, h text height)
Top Overlay:
  lines w10: 525.79,439.81 603.04,439.46
  text "PMP23126 GaN DC" at 25,1195 h72.83
  text "RevB" at 25,1130 h72.83
Mechanical 1:
  lines w10: 0,-120 0,0 0,1259.84 1302.44,1259.84 1305,1 1305,-119 1191,-119 1191,1 907.44,1 ; 0,-119 114,-119 ; 121.19,-119 121.19,1 199.93,1 199.93,-119 319.67,-119 ; 319.67,-120.93 319.67,-0.93 398.41,-0.93 398.41,-120.93 518.15,-120.93 518.15,-0.93 747.81,2.15 747.81,-117.85 ; 747.44,-119 907.44,-119 ; 906.71,-120.43 906.71,-0.43

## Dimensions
194.92,-119 to 126.21,-4.01 on Mechanical 16
194.92,-119 to 398.41,-125.95 on Mechanical 16
194.92,-119 to 523.17,-5.88 on Mechanical 16
194.92,-119 to 911.49,-121.96 on Mechanical 16
194.92,-119 to 911.73,-4.01 on Mechanical 16
194.92,-119 to 1310.01,-119 on Mechanical 16
126.21,-4.01 to 194.92,-4.01 on Mechanical 16
324.69,-120.93 to 315.72,-124.02 on Mechanical 16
